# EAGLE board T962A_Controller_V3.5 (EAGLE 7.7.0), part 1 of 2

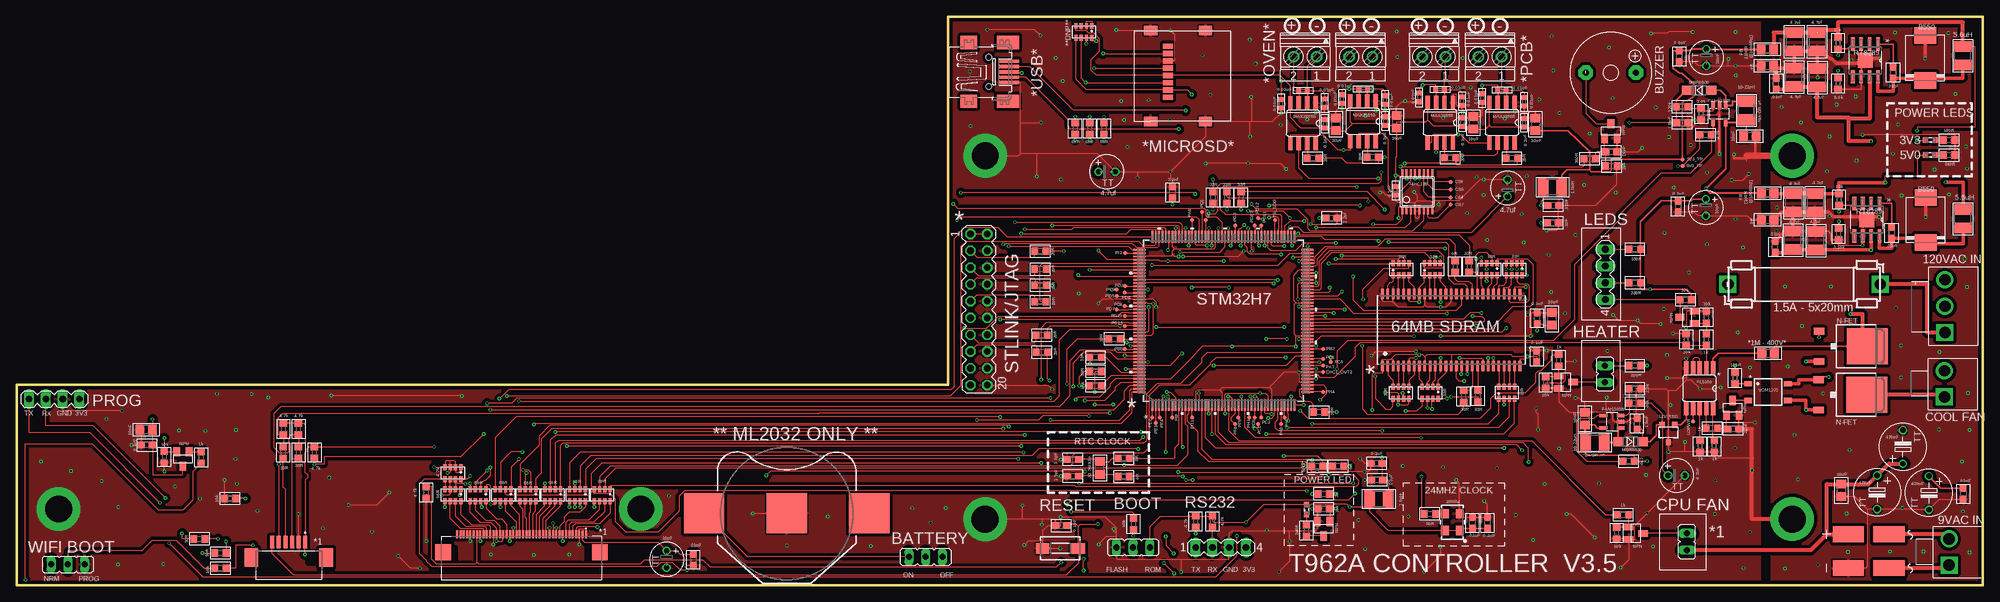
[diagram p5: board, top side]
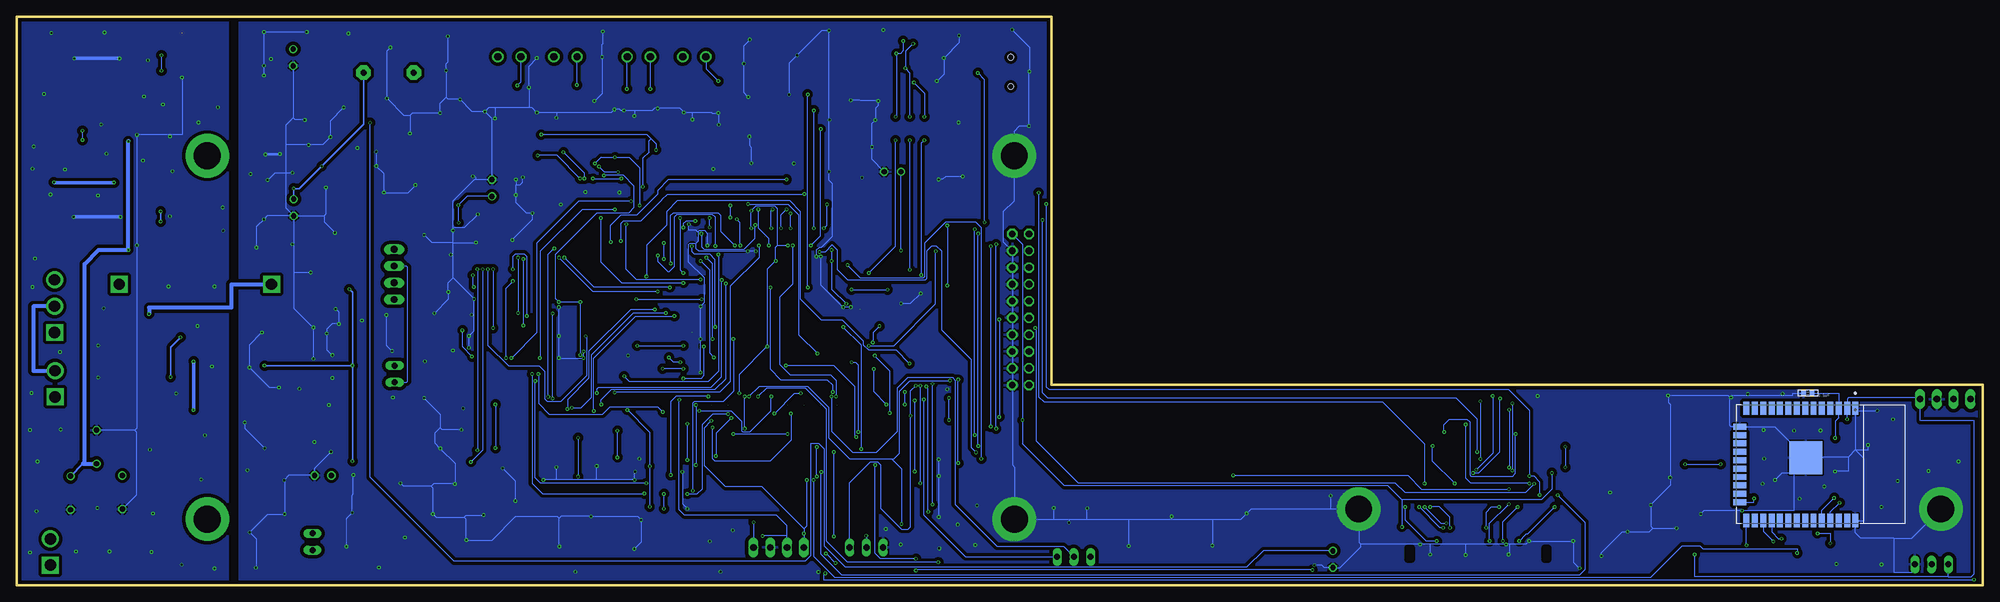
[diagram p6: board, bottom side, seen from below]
Size 297.71 x 86.11 mm. Coordinates in mm from the lower left corner, seen from the top.
Outline: 297.71,0 0,0 0,30.35 141,30.35 141,86.11 297.71,86.11 297.71,0
Copper layers (1*16): Top 0.035559375mm / dielectric 1.6mm / Bottom 0.035559375mm
Design rules "oshpark-2layer-tented": minimum track width 6mil, minimum drill 10mil, track to track 6mil, track to pad 6mil, pad to pad 6mil, via to via 6mil, smd to smd 6mil, copper to edge 15mil, drill to drill 6mil, minimum pad ring 5mil, minimum via ring 5mil, stop-mask expansion 2.5mil, vias tented up to drill 20mil, thermal gap 10mil

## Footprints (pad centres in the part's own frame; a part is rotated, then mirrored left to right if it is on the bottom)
Z4-D = smd 2.4 x 4.7: AC1 2.55,-3.1; AC2 -2.55,-3.1; VDD 2.55,3.1; VSS -2.55,3.1
BATTCON_20MM = smd 6.07 x 6.07: 1 -12.5,0; 2 0,0; 3 12.5,0
TT5D7 = drill 0.813: + -2.54,0 | drill 0.813 octagon: - 2.54,0
C0603 = smd 1.1 x 1: 1 -0.85,0; 2 0.85,0
TT2D5 = drill 0.813: + -1.27,0 | drill 0.813 octagon: - 1.27,0
C0805 = smd 1.3 x 1.5: 1 -0.95,0; 2 0.95,0
C0402 = smd 0.7 x 0.9: 1 -0.65,0; 2 0.65,0
C1210 = smd 1.6 x 2.7: 1 -1.4,0; 2 1.4,0
SOD123 = smd 1.4 x 1.4: A -1.9,0; C 1.9,0
FUSE_HOLDER_5X20MM_1.78MM = drill 1.707 square: 1 -2.565,0; 2 20.498,0.025
SOT23-3 = smd 0.8 x 0.9: 1 -0.95,-1; 2 0.95,-1; 3 0,1.659
TSSOP16 = smd 0.305 x 0.991: 1 -2.275,-2.918; 2 -1.625,-2.918; 3 -0.975,-2.918; 4 -0.325,-2.918; 5 0.325,-2.918; 6 0.975,-2.918; 7 1.625,-2.918; 8 2.275,-2.918; 9 2.275,2.918; 10 1.625,2.918; 11 0.975,2.918; 12 0.325,2.918; 13 -0.325,2.918; 14 -0.975,2.918; 15 -1.625,2.918; 16 -2.275,2.918
MOLEX_54104-4031-REV = smd 0.3 x 1.2: 1 9.75,0.6; 2 9.25,0.6; 3 8.75,0.6; 4 8.25,0.6; 5 7.75,0.6; 6 7.25,0.6; 7 6.75,0.6; 8 6.25,0.6; 9 5.75,0.6; 10 5.25,0.6; 11 4.75,0.6; 12 4.25,0.6; 13 3.75,0.6; 14 3.25,0.6; 15 2.75,0.6; 16 2.25,0.6; 17 1.75,0.6; 18 1.25,0.6; 19 0.75,0.6; 20 0.25,0.6; 21 -0.25,0.6; 22 -0.75,0.6; 23 -1.25,0.6; 24 -1.75,0.6; 25 -2.25,0.6; 26 -2.75,0.6; 27 -3.25,0.6; 28 -3.75,0.6; 29 -4.25,0.6; 30 -4.75,0.6; 31 -5.25,0.6; 32 -5.75,0.6; 33 -6.25,0.6; 34 -6.75,0.6; 35 -7.25,0.6; 36 -7.75,0.6; 37 -8.25,0.6; 38 -8.75,0.6; 39 -9.25,0.6; 40 -9.75,0.6 | smd 2.4 x 2.4: FITTING_NAIL_1 -11.85,-2.1; FITTING_NAIL_2 11.85,-2.1
KK41791-4020_2-PIN = drill 1.707 square: 1 -1.981,0 | drill 1.707: 2 1.981,0
MOLEX_52271-0679_REV = smd 0.6 x 1.9: 1 2.5,3.5; 2 1.5,3.5; 3 0.5,3.5; 4 -0.5,3.5; 5 -1.5,3.5; 6 -2.5,3.5 | smd 2.1 x 2.8: FITTING_NAIL_1 -5.65,1.15; FITTING_NAIL_2 5.65,1.15
KK41791-4020_3-PIN = drill 1.707 square: 1 -1.981,0 | drill 1.707: 2 1.981,0; 3 5.994,0
JP2_NOLABEL = drill 0.914 long: 1 -2.54,0; 2 0,0; 3 2.54,0
JP1 = drill 0.914 long: 1 0,-1.27; 2 0,1.27
L0805 = smd 1.3 x 1.5: 1 -0.95,0; 2 0.95,0
R1210 = smd 1.6 x 2.7: 1 -1.4,0; 2 1.4,0
SML0603 = smd 0.8 x 0.8: A 0.75,0; C -0.75,0
R0603 = smd 1 x 1.1: 1 -0.85,0; 2 0.85,0
R0805 = smd 1.3 x 1.5: 1 -0.95,0; 2 0.95,0
742-8NS-REV = smd 0.5 x 0.9: 1 1.2,-0.9; 2 0.4,-0.9; 3 -0.4,-0.9; 4 -1.2,-0.9; 5 -1.2,0.9; 6 -0.4,0.9; 7 0.4,0.9; 8 1.2,0.9
742-8NS = smd 0.5 x 0.9: 1 -1.2,-0.9; 2 -0.4,-0.9; 3 0.4,-0.9; 4 1.2,-0.9; 5 1.2,0.9; 6 0.4,0.9; 7 -0.4,0.9; 8 -1.2,0.9
DTSM-3 = smd 2 x 1.6: 1 -2.7,0; 2 2.7,0
YHE12-XX-7.6MM = drill 0.914 pad 2.159 octagon: + 3.81,0.025; - -3.81,0.025
MA10-2 = drill 1.016 octagon: 1 -11.43,-1.27; 2 -11.43,1.27; 3 -8.89,-1.27; 4 -8.89,1.27; 5 -6.35,-1.27; 6 -6.35,1.27; 7 -3.81,-1.27; 8 -3.81,1.27; 9 -1.27,-1.27; 10 -1.27,1.27; 11 1.27,-1.27; 12 1.27,1.27; 13 3.81,-1.27; 14 3.81,1.27; 15 6.35,-1.27; 16 6.35,1.27; 17 8.89,-1.27; 18 8.89,1.27; 19 11.43,-1.27; 20 11.43,1.27
MA04-1-VANILLA = drill 1.016 long: 1 -3.81,0; 2 -1.27,0; 3 1.27,0; 4 3.81,0
MA04-1 = drill 1.016 long: 1 -3.81,0; 2 -1.27,0; 3 1.27,0; 4 3.81,0
SOT23-BEC = smd 1 x 1.4: B -0.95,-1.1; C 0,1.1; E 0.95,-1.1
TP06R = smd 0.6 x 0.6: TP 0,0
LQFP176-24X24MM-M = smd 1.778 x 0.279: 1 -12.725,10.75; 2 -12.725,10.25; 3 -12.725,9.75; 4 -12.725,9.25; 5 -12.725,8.75; 6 -12.725,8.25; 7 -12.725,7.75; 8 -12.725,7.25; 9 -12.725,6.75; 10 -12.725,6.25; 11 -12.725,5.75; 12 -12.725,5.25; 13 -12.725,4.75; 14 -12.725,4.25; 15 -12.725,3.75; 16 -12.725,3.25; 17 -12.725,2.75; 18 -12.725,2.25; 19 -12.725,1.75; 20 -12.725,1.25; 21 -12.725,0.75; 22 -12.725,0.25; 23 -12.725,-0.25; 24 -12.725,-0.75; 25 -12.725,-1.25; 26 -12.725,-1.75; 27 -12.725,-2.25; 28 -12.725,-2.75; 29 -12.725,-3.25; 30 -12.725,-3.75; 31 -12.725,-4.25; 32 -12.725,-4.75; 33 -12.725,-5.25; 34 -12.725,-5.75; 35 -12.725,-6.25; 36 -12.725,-6.75; 37 -12.725,-7.25; 38 -12.725,-7.75; 39 -12.725,-8.25; 40 -12.725,-8.75; 41 -12.725,-9.25; 42 -12.725,-9.75; 43 -12.725,-10.25; 44 -12.725,-10.75; 89 12.725,-10.75; 90 12.725,-10.25; 91 12.725,-9.75; 92 12.725,-9.25; 93 12.725,-8.75; 94 12.725,-8.25; 95 12.725,-7.75; 96 12.725,-7.25; 97 12.725,-6.75; 98 12.725,-6.25; 99 12.725,-5.75; 100 12.725,-5.25; 101 12.725,-4.75; 102 12.725,-4.25; 103 12.725,-3.75; 104 12.725,-3.25; 105 12.725,-2.75; 106 12.725,-2.25; 107 12.725,-1.75; 108 12.725,-1.25; 109 12.725,-0.75; 110 12.725,-0.25; 111 12.725,0.25; 112 12.725,0.75; 113 12.725,1.25; 114 12.725,1.75; 115 12.725,2.25; 116 12.725,2.75; 117 12.725,3.25; 118 12.725,3.75; 119 12.725,4.25; 120 12.725,4.75; 121 12.725,5.25; 122 12.725,5.75; 123 12.725,6.25; 124 12.725,6.75; 125 12.725,7.25; 126 12.725,7.75; 127 12.725,8.25; 128 12.725,8.75; 129 12.725,9.25; 130 12.725,9.75; 131 12.725,10.25; 132 12.725,10.75 | smd 0.279 x 1.778: 45 -10.75,-12.725; 46 -10.25,-12.725; 47 -9.75,-12.725; 48 -9.25,-12.725; 49 -8.75,-12.725; 50 -8.25,-12.725; 51 -7.75,-12.725; 52 -7.25,-12.725; 53 -6.75,-12.725; 54 -6.25,-12.725; 55 -5.75,-12.725; 56 -5.25,-12.725; 57 -4.75,-12.725; 58 -4.25,-12.725; 59 -3.75,-12.725; 60 -3.25,-12.725; 61 -2.75,-12.725; 62 -2.25,-12.725; 63 -1.75,-12.725; 64 -1.25,-12.725; 65 -0.75,-12.725; 66 -0.25,-12.725; 67 0.25,-12.725; 68 0.75,-12.725; 69 1.25,-12.725; 70 1.75,-12.725; 71 2.25,-12.725; 72 2.75,-12.725; 73 3.25,-12.725; 74 3.75,-12.725; 75 4.25,-12.725; 76 4.75,-12.725; 77 5.25,-12.725; 78 5.75,-12.725; 79 6.25,-12.725; 80 6.75,-12.725; 81 7.25,-12.725; 82 7.75,-12.725; 83 8.25,-12.725; 84 8.75,-12.725; 85 9.25,-12.725; 86 9.75,-12.725; 87 10.25,-12.725; 88 10.75,-12.725; 133 10.75,12.725; 134 10.25,12.725; 135 9.75,12.725; 136 9.25,12.725; 137 8.75,12.725; 138 8.25,12.725; 139 7.75,12.725; 140 7.25,12.725; 141 6.75,12.725; 142 6.25,12.725; 143 5.75,12.725; 144 5.25,12.725; 145 4.75,12.725; 146 4.25,12.725; 147 3.75,12.725; 148 3.25,12.725; 149 2.75,12.725; 150 2.25,12.725; 151 1.75,12.725; 152 1.25,12.725; 153 0.75,12.725; 154 0.25,12.725; 155 -0.25,12.725; 156 -0.75,12.725; 157 -1.25,12.725; 158 -1.75,12.725; 159 -2.25,12.725; 160 -2.75,12.725; 161 -3.25,12.725; 162 -3.75,12.725; 163 -4.25,12.725; 164 -4.75,12.725; 165 -5.25,12.725; 166 -5.75,12.725; 167 -6.25,12.725; 168 -6.75,12.725; 169 -7.25,12.725; 170 -7.75,12.725; 171 -8.25,12.725; 172 -8.75,12.725; 173 -9.25,12.725; 174 -9.75,12.725; 175 -10.25,12.725; 176 -10.75,12.725
MODULE_ESP32-WROOM-32D = smd 2 x 0.9: 1 -8.5,5.26; 2 -8.5,3.99; 3 -8.5,2.72; 4 -8.5,1.45; 5 -8.5,0.18; 6 -8.5,-1.09; 7 -8.5,-2.36; 8 -8.5,-3.63; 9 -8.5,-4.9; 10 -8.5,-6.17; 11 -8.5,-7.44; 12 -8.5,-8.71; 13 -8.5,-9.98; 14 -8.5,-11.25; 25 8.5,-11.25; 26 8.5,-9.98; 27 8.5,-8.71; 28 8.5,-7.44; 29 8.5,-6.17; 30 8.5,-4.9; 31 8.5,-3.63; 32 8.5,-2.36; 33 8.5,-1.09; 34 8.5,0.18; 35 8.5,1.45; 36 8.5,2.72; 37 8.5,3.99; 38 8.5,5.26 | smd 0.9 x 2: 15 -5.715,-12.25; 16 -4.445,-12.25; 17 -3.175,-12.25; 18 -1.905,-12.25; 19 -0.635,-12.25; 20 0.635,-12.25; 21 1.905,-12.25; 22 3.175,-12.25; 23 4.445,-12.25; 24 5.715,-12.25 | smd 5 x 5: 39 -1,-2.24
SOT23-5L = smd 0.55 x 1.2: 1 -0.95,-1.3; 2 0,-1.3; 3 0.95,-1.3; 4 0.95,1.3; 5 -0.95,1.3
SO08 = smd 0.66 x 2.032: 1 -1.905,-3.073; 2 -0.635,-3.073; 3 0.635,-3.073; 4 1.905,-3.073; 5 1.905,3.073; 6 0.635,3.073; 7 -0.635,3.073; 8 -1.905,3.073
SOIC127P600X175-9N = smd 1.981 x 0.559: 1 -2.464,1.905; 2 -2.464,0.635; 3 -2.464,-0.635; 4 -2.464,-1.905; 5 2.464,-1.905; 6 2.464,-0.635; 7 2.464,0.635; 8 2.464,1.905 | smd 2.286 x 2.286: 9 0,0
DO214AB-SMC = smd 2.5 x 3.3: A 3.4,0; C -3.4,0
SOP10 = smd 0.66 x 2.032: 1 -2.057,-3.073; 2 -1.041,-3.073; 3 -0.025,-3.073; 4 0.991,-3.073; 5 2.007,-3.073; 6 2.007,3.073; 7 0.991,3.073; 8 -0.025,3.073; 9 -1.041,3.073; 10 -2.057,3.073
DPACK_3 = smd 1 x 1.6: 1 -2.28,-4.8; 3 2.28,-4.8 | smd 5.4 x 6.2: 4 0,2.5
SOP04 = smd 0.8 x 1.2: 1 -1.27,-3; 2 1.27,-3; 3 1.27,3; 4 -1.27,3
TSOP54 = smd 0.4 x 1.6: 1 -10.4,-5.45; 2 -9.6,-5.45; 3 -8.8,-5.45; 4 -8,-5.45; 5 -7.2,-5.45; 6 -6.4,-5.45; 7 -5.6,-5.45; 8 -4.8,-5.45; 9 -4,-5.45; 10 -3.2,-5.45; 11 -2.4,-5.45; 12 -1.6,-5.45; 13 -0.8,-5.45; 14 0,-5.45; 15 0.8,-5.45; 16 1.6,-5.45; 17 2.4,-5.45; 18 3.2,-5.45; 19 4,-5.45; 20 4.8,-5.45; 21 5.6,-5.45; 22 6.4,-5.45; 23 7.2,-5.45; 24 8,-5.45; 25 8.8,-5.45; 26 9.6,-5.45; 27 10.4,-5.45; 28 10.4,5.45; 29 9.6,5.45; 30 8.8,5.45; 31 8,5.45; 32 7.2,5.45; 33 6.4,5.45; 34 5.6,5.45; 35 4.8,5.45; 36 4,5.45; 37 3.2,5.45; 38 2.4,5.45; 39 1.6,5.45; 40 0.8,5.45; 41 0,5.45; 42 -0.8,5.45; 43 -1.6,5.45; 44 -2.4,5.45; 45 -3.2,5.45; 46 -4,5.45; 47 -4.8,5.45; 48 -5.6,5.45; 49 -6.4,5.45; 50 -7.2,5.45; 51 -8,5.45; 52 -8.8,5.45; 53 -9.6,5.45; 54 -10.4,5.45
MOLEX:47219-2001 = smd 1.45 x 2: G1 13.75,0; G2 13.75,8.3; G3 0,8.3; G4 0,0 | smd 0.8 x 1.5: P1 10.08,2.6; P2 8.98,2.6; P3 7.88,2.6; P4 6.78,2.6; P5 5.68,2.6; P6 4.58,2.6; P7 3.48,2.6; P8 2.38,2.6
1751248 = drill 1.1 pad 1.7: 1 -1.75,-0.1; 2 1.75,-0.1
32005-201 = smd 3.1 x 0.5: 1 3,1.6; 2 3,0.8; 3 3,0; 4 3,-0.8; 5 3,-1.6 | smd 2.5 x 2: M1 -3,-4.45; M2 -3,4.45 | smd 3.3 x 2: M3 2.9,4.45; M4 2.9,-4.45 | hole 0.9: 0,2.2; 0,-2.2
OSCILLATOR-SMD-5X3.2 = smd 1.397 x 1.194: 1 -1.27,-1.1; 2 1.27,-1.1; 3 1.27,1.1; 4 -1.27,1.1

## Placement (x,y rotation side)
B1  Z4DGP406L-HF  [Z4-D]  280.39,5.18 90 top
BT1  [BATTCON_20MM]  116.61,10.9 0 top
C1  470uF  [TT5D7]  289.53,14 270 top
C2  0.1uF  [C0603]  205.89,18.47 180 top
C3  10uF  [TT2D5]  255.83,79.91 270 top
C4  0.01uF  [C0603]  205.97,15.98 180 top
C5  .1uf  [C0603]  158.17,9.04 180 top
C6  470uF  [TT5D7]  281.69,14.1 270 top
C7  10uF  [C0805]  276.28,14.38 270 top
C8  0.1uF  [C0603]  222.71,9.47 90 top
C9  2.2uF  [C0603]  175.01,59.49 90 top
C10  2.2uF  [C0603]  199.09,55.63 0 top
C11  10uF  [TT2D5]  255.75,57.2 270 top
C12  0.01uF  [C0603]  220.42,9.47 90 top
C13  .1uf  [C0603]  230.2,40.44 90 top
C14  .1uf  [C0603]  230.15,34.65 90 top
C15  1.0uF  [C0603]  252.17,70.03 0 top
C16  0.1uF  [C0603]  251.71,80.09 270 top
C17  0.1uF  [C0603]  251.54,57.35 270 top
C18  10uF  [C0805]  262.41,67.97 0 top
C19  0.01uF  [C0402]  203.89,75.16 180 top
C20  0.01uF  [C0402]  200.66,73.61 90 top
C21  0.01uF  [C0402]  207.19,73.46 90 top
C22  0.01uF  [C0402]  215.52,75.06 180 top
C23  0.01uF  [C0402]  212.37,73.86 90 top
C24  1.5pf  [C0603]  159.92,19.08 0 top
C25  1.5pf  [C0603]  159.92,16.56 0 top
C26  0.1uF  [C0603]  232.61,54.89 0 top
C27  22nf  [C0603]  259.89,23.7 180 top
C28  470uF  [TT5D7]  285.6,20.95 90 top
C29  0.01uF  [C0603]  232.66,57.53 0 top
C30  1.0uF  [C0603]  245.34,24.49 90 top
C31  0.1uF  [C0402]  208.79,59.74 270 top
C32  0.1uF  [C0402]  207.21,70.28 270 top
C33  0.1uF  [C0402]  218.87,70.13 270 top
C34  10uF  [C0805]  237.44,25.25 90 top
C35  0.1uF  [C0402]  228.24,70.03 270 top
C36  0.1uF  [C0402]  198.07,69.88 270 top
C37  4.7uF  [TT2D5]  251.31,16.64 0 top
C38  4.7uF  [TT2D5]  165.07,62.61 0 top
C39  4.7uF  [TT2D5]  225.73,60.15 90 top
C40  10uF  [TT2D5]  98.42,3.96 270 top
C41  .01uF  [C0603]  102.44,3.89 270 top
C42  10uF  [C0805]  232.46,40.34 90 top
C43  10uF  [C0805]  19.66,23.55 180 top
C44  0.1uF  [C0603]  19.74,21.23 180 top
C45  DNP  [C0603]  241.43,65.63 180 top
C46  10uF  [C0805]  199.72,69.8 270 top
C47  10uF  [C0805]  208.94,70.15 270 top
C48  0.01uF  [C0402]  191.44,72.92 90 top
C49  10uF  [C0805]  220.55,70.03 270 top
C50  .01uF  [C0603]  294.72,13.87 270 top
C51  10uF  [C0805]  229.97,69.8 270 top
C52  0.01uF  [C0402]  198.04,73 90 top
C53  0.01uF  [C0402]  194.77,74.88 180 top
C54  .01uF  [C0603]  284.1,77.62 270 top
C55  .01uF  [C0603]  266.4,75.95 90 top
C56  4.7uF  [C1210]  272.64,76.84 90 top
C57  4.7uF  [C1210]  269.09,76.91 90 top
C58  47uf  [C1210]  269.14,82.27 270 top
C59  47uf  [C1210]  272.59,82.27 270 top
C60  0.01uF  [C0402]  218.85,73.28 90 top
C61  0.01uF  [C0402]  224.89,74.98 180 top
C62  0.01uF  [C0402]  221.89,73.76 90 top
C63  0.01uF  [C0402]  228.24,73.2 90 top
C64  0.1uF  [C0402]  26.52,29.08 180 bottom
C88  .01uF  [C0603]  283.87,53.37 270 top
C89  .01uF  [C0603]  266.24,51.23 90 top
C90  4.7uF  [C1210]  272.41,52.17 90 top
C91  4.7uF  [C1210]  268.94,52.25 90 top
C92  47uf  [C1210]  272.29,57.94 270 top
C93  47uf  [C1210]  269.01,57.89 270 top
D1  MBR0520LT  [SOD123]  254.71,74.93 180 top
D2  MBR0520LT  [SOD123]  244.35,21.74 0 top
F1  FUSE  [FUSE_HOLDER_5X20MM_1.78MM]  261.67,45.57 0 top
IC1  TLV760SOT-23-3  [SOT23-3]  250.09,23.32 180 top
IC2  74138TSSOP  [TSSOP16]  212.06,59.56 0 top
J1  54104-4031MOLEX_54101_4031-REV  [MOLEX_54104-4031-REV]  76.45,7.11 0 top
J2  0026604020  [KK41791-4020_2-PIN]  292.58,5.05 90 top
J3  52271-0679_REVMOLEX_52271-0679-REV  [MOLEX_52271-0679_REV]  41.22,3.1 0 top
J4  0026604030  [KK41791-4020_3-PIN]  291.95,40.26 90 top
J5  0026604020  [KK41791-4020_2-PIN]  291.87,30.51 90 top
JP1  [JP2_NOLABEL]  169.04,5.74 0 top
JP2  [JP1]  240.46,32 0 top
JP3  [JP1]  252.88,6.6 180 top
JP4  [JP2_NOLABEL]  137.64,4.32 180 top
JP6  [JP2_NOLABEL]  7.77,3.17 180 top
L1  100R@100Mhz  [L0805]  265.1,59.36 180 top
L2  5.6uH  [R1210]  294.67,80.16 90 top
L3  5.6uH  [R1210]  294.69,55.47 90 top
L4  10uH  [R1210]  206.27,13.11 0 top
L6  100R@100Mhz  [L0805]  265.07,81.18 180 top
L8  10uH  [R1210]  232.54,60.27 180 top
LED1  [SML0603]  289.74,67.41 180 top
LED2  [SML0603]  195.3,11.48 90 top
LED5  [SML0603]  289.71,65.13 180 top
Q1  32.768Khz  [C0805]  164.01,17.78 90 top
R1  20R  [R0603]  154.99,50.57 180 top
R2  100R  [R0603]  292.56,67.41 0 top
R3  20R  [R0603]  155.02,47.88 180 top
R4  20R  [R0603]  155.02,45.42 180 top
R5  240R  [R0603]  292.58,65.13 180 top
R6  0R  [R0805]  265.1,55.37 180 top
R7  20R  [R0603]  154.99,42.95 180 top
R8  20R  [R0603]  155.19,37.87 180 top
R9  20R  [R0603]  155.24,35.31 180 top
R10  10k  [R0603]  163.35,30.23 0 top
R11  10k  [R0603]  169.09,9.3 90 top
R12  33R  [R0603]  219.94,48.29 270 top
R13  0R  [R0603]  167.61,19.25 180 top
R14  50R  [R0603]  213.97,10.82 0 top
R15  0R  [R0603]  217.78,48.29 270 top
R16  33R  [R0603]  181.13,58.7 90 top
R17  20R  [R0603]  205.33,64.8 180 top
R18  20R  [R0603]  217.04,64.72 180 top
R19  20R  [R0603]  226.39,64.64 180 top
R20  1k  [R0603]  256.67,23.77 0 top
R21  10k  [R0603]  252.78,37.24 90 top
R22  100R  [R0603]  245.01,33.27 180 top
R23  4.7k  [R0603]  178.51,9.65 270 top
R24  4.7k  [R0603]  181.05,9.65 270 top
R25  100R  [R0603]  260.17,31.39 90 top
R26  2.0k  [R0603]  245.01,29.77 0 top
R27  20R  [R0603]  196.27,64.67 180 top
R28  2k  [R0603]  197.92,13.84 180 top
R29  240R  [R0603]  195.3,8.33 270 top
R30  10k  [R0603]  197.92,11.61 0 top
R31  10K  [R0603]  275.77,82.07 270 top
R32  5.6k  [R0603]  275.77,75.95 270 top
R33  10K  [R0603]  275.92,58.42 270 top
R34  3.16k  [R0603]  275.84,53.16 270 top
R35  10k  [R0603]  241.45,63.47 180 top
R36  4k7  [R0603]  42.7,23.67 90 top
R37  4K7  [R0603]  255.7,68.22 0 top
R38  4k7  [R0603]  62.03,14.05 270 top
R39  0R  [R0805]  265.07,78.66 180 top
R40  1M  [R0805]  265.18,35.15 0 top
R41  4k7  [R0603]  40.41,23.67 90 top
R42  33R  [R0603]  221.23,28.65 90 top
R43  390R  [R0603]  238.18,64.59 180 top
R44  10k  [R0603]  255.83,40.59 90 top
R45  120k  [R0603]  252.17,72.47 180 top
R46  4K7  [R0603]  244.04,18.8 180 top
R47  80k  [R0603]  245.01,27.56 0 top
R48  68R  [R0603]  164.64,69.16 90 top
R49  68R  [R0603]  162.48,69.16 90 top
R50  68R  [R0603]  160.27,69.16 90 top
R51  33R  [R0603]  42.7,20.12 270 top
R52  1k  [R0603]  243.2,10.69 0 top
R53  10k  [R0603]  242.24,7.9 90 top
R54  1k  [R0603]  233.48,34.09 270 top
R55  10k  [R0603]  231.5,30.71 90 top
R56  330R  [R0603]  245.01,50.88 180 top
R57  330R  [R0603]  245.01,45.8 180 top
R58  10k  [R0603]  252.7,43.23 0 top
R59  0R  [R0603]  200.08,18.03 0 top
R60  DNP  [R0603]  196.93,18.03 0 top
R61  2.0k  [R0603]  255.04,71.32 270 top
R62  1k  [R0603]  254.86,21.06 90 top
R63  1k  [R0603]  257.02,21.06 90 top
R64  1k  [R0603]  255.83,37.24 90 top
R65  33R  [R0603]  40.39,20.12 270 top
R66  4k7  [R0603]  45.11,20.12 90 top
R67  33R  [R0603]  219.07,28.63 90 top
R68  33R  [R0603]  166.22,37.34 180 top
R69  33R  [R0603]  197.21,26.24 0 top
R70  33R  [R0603]  163.35,34.54 180 top
R71  33R  [R0603]  163.35,32.38 180 top
R72  33R  [R0603]  183.26,58.7 90 top
R73  33R  [R0603]  185.39,58.7 90 top
R74  0R  [R0603]  167.61,16.48 180 top
R75  10k  [R0603]  22.38,19.41 270 top
R76  10k  [R0603]  30.89,2.59 0 top
R77  10k  [R0603]  32.33,13.16 0 top
R78  50R  [R0603]  30.89,4.9 0 top
R79  1k  [R0603]  27.97,19.38 270 top
R80  50R  [R0603]  27.69,7.04 0 top
RN1  33R  [742-8NS-REV]  209.63,47.83 0 top
RN2  33R  [742-8NS-REV]  214.35,47.83 0 top
RN3  33R  [742-8NS-REV]  214.02,29.16 180 top
RN4  33R  [742-8NS-REV]  209.6,29.16 180 top
RN5  33R  [742-8NS]  225.6,29.16 0 top
RN6  4.7k  [742-8NS]  66.07,16.99 180 top
RN7  33R  [742-8NS]  226.75,47.83 180 top
RN8  33R  [742-8NS]  222.96,47.83 180 top
RN11  **DNP**  [742-8NS]  161.59,83.77 180 top
RN12  68R  [742-8NS-REV]  88.67,13.67 180 top
RN13  68R  [742-8NS-REV]  84.94,13.67 180 top
RN14  68R  [742-8NS-REV]  81.18,13.67 180 top
RN15  68R  [742-8NS-REV]  77.42,13.67 180 top
RN16  68R  [742-8NS-REV]  73.66,13.67 180 top
RN17  68R  [742-8NS-REV]  69.88,13.67 180 top
RN18  68R  [742-8NS-REV]  66.07,13.67 180 top
S1  DTSM-3  [DTSM-3]  158.04,5.61 0 top
SG1  YHE12-XX7.6MM  [YHE12-XX-7.6MM]  241.38,77.6 0 top
SV1  [MA10-2]  145.69,41.76 270 top
SV2  PROG  [MA04-1-VANILLA]  5.71,28.19 0 top
SV3  [MA04-1]  240.54,47.07 270 top
SV5  RS232  [MA04-1]  182.32,5.74 0 top
T1  BC817-16LT1SMD  [SOT23-BEC]  241.38,68.76 0 top
T2  BC817-16LT1SMD  [SOT23-BEC]  25.2,19.13 180 top
T3  BC817-16LT1SMD  [SOT23-BEC]  197.89,8.59 180 top
T4  BC817-16LT1SMD  [SOT23-BEC]  245.16,7.87 270 top
T5  BC817-16LT1SMD  [SOT23-BEC]  234.57,30.76 270 top
T6  BC817-16LT1SMD  [SOT23-BEC]  259.82,26.87 0 top
T7  BC817-16LT1SMD  [SOT23-BEC]  252.93,40.59 90 top
TP1  TPTP06R  [TP06R]  187.48,25.43 0 top
TP2  TPTP06R  [TP06R]  187.99,24.41 0 top
TP3  TPTP06R  [TP06R]  198.93,33.78 0 top
TP4  TPTP06R  [TP06R]  252.22,64.47 0 top
TP5  TPTP06R  [TP06R]  188.47,25.43 0 top
TP6  TPTP06R  [TP06R]  217.12,57.66 0 top
TP7  TPTP06R  [TP06R]  217.12,61.09 0 top
TP8  TPTP06R  [TP06R]  217.12,59.92 0 top
TP9  TPTP06R  [TP06R]  217.12,58.75 0 top
TP10  TPTP06R  [TP06R]  197.79,34.29 90 top
TP11  TPTP06R  [TP06R]  167.77,42.27 0 top
TP12  TPTP06R  [TP06R]  166.55,41.78 0 top
TP13  TPTP06R  [TP06R]  173.05,25.43 0 top
TP15  TPTP06R  [TP06R]  171.96,25.43 0 top
TP16  TPTP06R  [TP06R]  179.5,56.54 90 top
TP17  TPTP06R  [TP06R]  180.04,55.27 90 top
TP18  TPTP06R  [TP06R]  197.79,32.28 0 top
TP19  TPTP06R  [TP06R]  197.79,33.27 0 top
TP21  TPTP06R  [TP06R]  177.98,55.27 0 top
TP22  TPTP06R  [TP06R]  197.79,35.76 0 top
TP23  TPTP06R  [TP06R]  167.77,35.79 0 top
TP24  TPTP06R  [TP06R]  167.82,45.29 0 top
TP25  TPTP06R  [TP06R]  166.55,44.78 0 top
TP26  TPTP06R  [TP06R]  167.77,39.29 0 top
TP27  TPTP06R  [TP06R]  252.22,63.45 0 top
TP28  TPTP06R  [TP06R]  253.8,24.79 0 top
TP29  TPTP06R  [TP06R]  191.47,24.41 0 top
TP30  TPTP06R  [TP06R]  191.99,25.43 0 top
TP31  TPTP06R  [TP06R]  167.77,44.3 0 top
TP32  TPTP06R  [TP06R]  166.55,43.81 0 top
TP33  TPTP06R  [TP06R]  184.48,24.41 0 top
TP34  TPTP06R  [TP06R]  184.96,25.43 0 top
TP35  TPTP06R  [TP06R]  167.77,40.79 0 top
TP36  TPTP06R  [TP06R]  197.79,29.29 0 top
TP39  TPTP06R  [TP06R]  184.48,54.48 0 top
TP40  TPTP06R  [TP06R]  167.82,50.29 0 top
TP41  TPTP06R  [TP06R]  174.98,25.43 0 top
TP42  TPTP06R  [TP06R]  188.47,54.48 0 top
TP43  TPTP06R  [TP06R]  187.96,55.63 0 top
TP44  TPTP06R  [TP06R]  187.48,54.48 0 top
TP45  TPTP06R  [TP06R]  177.98,25.43 0 top
TP46  TPTP06R  [TP06R]  190.55,55.27 0 top
TP47  TPTP06R  [TP06R]  186.61,25.43 0 top
TP48  TPTP06R  [TP06R]  172.47,24.56 0 top
U1  STM32H7X3IITLQFP176-24X24MM-M  [LQFP176-24X24MM-M]  182.73,40.03 90 top
U2  ESP32-WROOM-32D  [MODULE_ESP32-WROOM-32D]  24.56,18.31 270 bottom
U$1  FAN5333ABSOT23-5  [SOT23-5L]  257.81,71.4 180 top
U$2  INDUCTOR-GENERIC1210-PKG  [R1210]  261.9,71.88 90 top
U$3  MAX31855  [SO08]  194.77,69.95 180 top
U$4  MAX31855  [SO08]  203.83,70.23 180 top
U$5  MAX31855  [SO08]  215.54,70.05 180 top
U$6  MAX31855  [SO08]  224.89,70.05 180 top
U$7  RT8289  [SOIC127P600X175-9N]  279.91,79.48 270 top
U$8  DIODE-SMC  [DO214AB-SMC]  288.98,79.83 90 top
U$9  RT8289  [SOIC127P600X175-9N]  280.14,55.35 270 top
U$10  FL5160SOP10  [SOP10]  254.79,29.82 180 top
U$11  N-PWR-MOSFETDPAK3  [DPACK_3]  277.65,28.85 270 top
U$12  N-PWR-MOSFETDPAK3  [DPACK_3]  277.67,36.2 270 top
U$13  DIODE-SMC  [DO214AB-SMC]  289.05,55.32 90 top
U$14  VOM1271  [SOP04]  265.15,29.26 270 top
U$15  AS4C32M16SB  [TSOP54]  217.2,38.66 0 top
U$16  INDUCTOR-GENERIC1210-PKG  [R1210]  238.94,21.62 0 top
U$17  FAN5333ABSOT23-5  [SOT23-5L]  241.55,24.77 90 top
U$19  MOLEX-47219-2001  [MOLEX:47219-2001]  171.7,83.97 270 top
X1  1751248  [1751248]  195.1,79.93 180 top
X2  1751248  [1751248]  203.5,79.93 180 top
X3  1751248  [1751248]  214.6,79.93 180 top
X4  1751248  [1751248]  223.09,79.93 180 top
X5  MINI-USB-32005-201  [32005-201]  147.19,77.72 0 top
Y1  OSCILLATORSMD-5X3  [OSCILLATOR-SMD-5X3.2]  217.37,9.58 90 top

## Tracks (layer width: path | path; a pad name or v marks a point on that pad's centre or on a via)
3V3_VDD  (via drill 0.25 pad 0.51)
  Top 0.152: 204.87,11.91 v201.85,11.91 201.37,12.39 196.1,12.39 195.94,12.23 LED2.A 188.81,12.23 v186.13,9.55 181.25,9.55 181.05,9.75 R24.1 R23.1 173.19,10.5 171.58,8.89 JP1.3 | 204.87,11.91 204.87,11.15 207.72,8.31 Y1.4 Y1.1 218.47,8.62 C12.1 C8.1 | 213.64,70.41 213.33,70.1 208.94,70.1 208.94,69.63 | 208.94,69.63 C32.2 207.21,69.88 202.23,69.88 | 161.99,83.92 161.19,83.92 | 161.19,83.92 160.39,83.92 RN11.4 | 161.19,83.92 RN11.3 | 161.99,83.92 162.35,83.57 163.14,83.57 163.96,82.75 163.96,80.87 162.66,79.58 162.66,78.01 163.47,77.19 U$19.P4 191.26,77.19 192.86,75.59 U$3.4 192.86,70.83 194.46,69.23 C36.2 199.72,69.23 C46.2 201.21,68.85 202.23,69.88 | v228.75,34.65 230.15,34.65 C14.1 | v228.75,34.65 226.57,34.65 226.31,34.9 217.2,34.9 | 217.2,34.9 213.51,34.9 213.21,34.59 | v162.36,25.68 155.37,25.68 154.71,25.02 v145.42,25.02 | 217.2,34.9 U$15.14 | v208.79,62.05 208.79,64.72 208.94,64.87 C47.2 208.94,69.63 | v208.79,62.05 C31.1 | 213.64,70.41 214.57,69.48 C33.2 219.56,69.48 219.56,69.08 C49.2 222.36,69.08 222.96,69.68 | 222.96,69.68 223.27,69.38 C35.2 228.93,69.38 228.93,68.85 C51.2 | 44.04,20.45 43.74,20.75 43.74,24.32 43.54,24.52 R36.2 R41.2 | 208.1,34.24 208.76,34.9 v212.34,34.9 212.9,34.9 213.21,34.59 | 204.87,11.91 L4.1 | 44.04,20.45 43.74,20.14 43.74,17.07 44.04,16.76 44.04,16.33 43.72,16.01 J3.1 43.66,6.6 v43.66,4.67 | 44.04,20.45 44.04,20.75 44.26,20.97 R66.2 63.22,20.97 v63.22,20.98 | v230.2,38.61 C13.1 230.94,39.59 231.14,39.38 C42.1 | 161.99,83.92 RN11.2 161.99,85.37 162.79,85.37 RN11.1 | 65.2,16.94 v65.28,17.02 65.51,17.02 65.76,17.27 65.76,17.89 RN6.3 65.67,18.88 65.68,18.9
  Top 0.152: 222.96,69.68 222.98,69.7 222.99,69.7 U$6.4 | 202.23,69.88 201.93,70.18 U$4.4 | 213.64,70.41 U$5.4 | 65.68,18.9 65.07,18.9 64.87,18.69 RN6.4 v63.22,17.88 | 65.68,18.9 66.26,18.9 66.47,18.69 RN6.2 66.47,17.09 67.27,17.09 RN6.1 | SV1.2 SV1.1 | v208.79,62.05 209.27,62.05 209.27,61.95 209.47,61.75 209.79,61.75 IC2.16 | v205.23,26.57 205.23,31.93 205.44,32.13 206.8,32.13 U$15.1 206.8,34.24 208.1,34.24 | v228.75,34.65 228.35,34.24 227.6,34.24 U$15.27 | 213.21,34.59 213.21,34.27 213.2,34.25 U$15.9 | 208.1,34.24 208.41,34.24 208.41,33.21 U$15.3 | v87.96,8.86 84.91,8.86 84.7,8.66 J1.4 | v212.34,42.9 210.97,42.9 210.8,43.08 U$15.49 | v201.85,18.03 R59.2 | v161.57,30.23 R10.1 | v215.6,42.9 | v215.6,42.9 U$15.43 | C44.1 20.61,21.23 | 20.61,21.23 C43.1 v20.61,25.15 v20.6,25.15 | 20.61,21.23 20.61,16.71 25.17,16.71 25.17,18.03 T2.C
  Top 0.203: 253.9,74.07 252.93,73.36 252.43,73.36 252.17,73.05 TP4.TP 241.48,64.47 241.48,62.89 241.3,62.59 238.38,62.59 238.18,62.89 | C51.2 234.9,68.85 238.18,65.67 238.18,62.89 | 238.18,62.89 234.75,62.89 233.94,62.18 L8.1
  Top 0.254: C16.1 250.72,80.94 250.72,78.31 251.79,77.5 252.15,77.5 253.9,75.9 253.9,74.07
  Top 0.305: L6.2 C3.+ 253.57,81.18 253.33,80.94 C16.1
  Bottom 0.152: JP1.3 171.58,15.52 168.4,18.69 167.34,18.69 166.93,18.29 166.93,11.66 163.75,8.48 162.76,8.48 162.36,8.89 v162.36,25.68 162.36,29.44 v161.57,30.23 | 87.96,12.93 90.12,15.09 139.07,15.09 145.42,21.44 v145.42,25.02 145.42,51.64 SV1.2 | v65.28,17.02 65.28,14.53 66.88,12.93 87.96,12.93 | v208.79,62.05 205.79,62.05 204.19,60.45 204.19,57.2 205,56.39 209.78,56.39 216.08,50.09 216.08,43.38 v215.6,42.9 v212.34,42.9 v212.34,34.9 | v186.13,9.55 SV5.4 | v228.75,34.65 230.2,36.09 v230.2,38.61 | v205.23,26.57 201.85,23.19 v201.85,18.03 v201.85,11.91 | 87.96,12.93 v87.96,8.86 | v63.22,20.98 v63.22,17.88 | v20.6,25.15 20.6,26.81 U2.2 20.57,28.17 20.37,28.37 9.53,28.37 SV2.4 9.53,24.92 1.35,24.92 1.35,1.78 1.78,1.35 5.23,1.35 | 5.23,1.35 JP6.3 | 5.23,1.35 43.66,1.35 v43.66,4.67
5V0_VDD  (via drill 0.25 pad 0.51)
  Top 0.152: R37.1 254.85,66.08 TP27.TP v251.51,63.45 | 261.9,69.98 U$2.1 261.9,70.93 | 261.9,67.97 C18.1 | v246.84,33.27 R22.1 | 237.54,24.3 C34.1
  Top 0.203: 261.9,69.98 261.9,67.97
  Top 0.254: 237.54,24.3 238.86,24.3 239.34,23.81 U$17.5 | U$16.1 237.54,19.99 237.94,19.71 244.89,19.71 R46.1 v246.84,18.8 | R58.2 253.55,44.03 252.76,44.83 v247.32,44.83 246.01,44.83 245.86,44.98 R57.1 R56.1 245.86,55.02 249.05,58.2 C17.1 253.53,58.2 253.8,58.47 C11.+ | U$1.5 258.76,63.08 v255.75,60.07 | v260.17,33.27 R25.2
  Top 0.305: 264.1,59.31 L1.2 256.46,59.36 v255.75,60.07 | U$16.1 237.54,24.3 | U$1.5 261.9,70.1 261.9,69.98
  Bottom 0.203: SG1.+ 245.19,69.77 v251.51,63.45 254.89,60.07 v255.75,60.07
  Bottom 0.254: C11.+ v255.75,60.07 | v246.84,33.27 v246.84,18.8 | v246.84,33.27 v260.17,33.27 | v247.32,44.83 246.84,44.35 v246.84,33.27
12V0_VDD
  Top 0.203: U$10.6 252.78,25.12 251.98,24.32 IC1.1
!CS0  (via drill 0.25 pad 0.51)
  Top 0.152: v206.15,61.57 195.73,61.57 194.13,63.17 U$3.6 | v210.44,61.57 | v210.44,61.57 IC2.15
  Bottom 0.152: v210.44,61.57 v206.15,61.57
!CS1
  Top 0.152: U$4.6 203.2,68.4 206.78,68.4 207.59,67.59 207.59,60.1 208,59.69 209.5,59.69 211.09,61.28 IC2.14
!CS2  (via drill 0.25 pad 0.51)
  Top 0.152: v214.91,65.56 U$5.6 | v211.73,61.57 v211.74,61.57 IC2.13
  Bottom 0.152: v211.73,61.57 211.73,62.38 v214.91,65.56
!CS3  (via drill 0.25 pad 0.51)
  Top 0.152: v218.82,65.08 223.85,65.08 224.26,65.48 U$6.6 | v212.39,61.57 IC2.12
  Bottom 0.152: v212.39,61.57 215.9,65.08 v218.82,65.08
!CS4
  Top 0.152: TP9.TP 213.84,58.75 213.04,59.55 IC2.11
!CS5
  Top 0.152: TP8.TP 214.5,59.92 213.69,60.73 IC2.10
!CS6
  Top 0.152: TP7.TP 214.76,61.09 214.34,61.5 IC2.9
!CS7
  Top 0.152: TP6.TP 215.06,55.6 213.89,55.6 213.69,55.8 IC2.7
!TP_INT  (via drill 0.25 pad 0.51)
  Top 0.152: v70.76,22.94 67.27,19.45 46.58,19.45 46.58,18.34 v45.11,18.34 R66.1 | v170.28,23.24 v81.58,23.24 | v39.73,18.34 39.73,7.09 39.72,7.09 J3.5 | v171.3,33.78 U1.167
  Bottom 0.152: v81.58,23.24 v81.59,23.25 81.59,24.33 80.78,25.15 78.11,25.15 77.7,24.74 77.7,16.74 77.5,16.54 71.17,16.54 70.76,16.94 v70.76,22.94 | v171.3,33.78 170.69,33.78 170.28,33.38 v170.28,23.24 | v45.11,18.34 v39.73,18.34
A0  (via drill 0.25 pad 0.51)
  Top 0.152: v196.16,19 181.08,19 179.48,20.6 U1.16 | v196.16,24.46 222.81,24.46 224.4,26.05 RN5.1
  Bottom 0.152: v196.16,24.46 v196.17,24.46 v196.17,19 v196.16,19
A1  (via drill 0.25 pad 0.51)
  Top 0.152: v225.2,20.78 181.58,20.78 179.98,22.38 U1.17 | v225.2,27.38 v225.2,27.39 RN5.2
  Bottom 0.152: v225.2,27.38 v225.2,20.78
A2  (via drill 0.25 pad 0.51)
  Top 0.152: v192.33,23.9 224.41,23.9 226,25.49 RN5.3 | v180.47,26.01 180.48,26.02 U1.18
  Bottom 0.152: v180.47,26.01 180.47,21.97 183.64,18.8 191.92,18.8 192.33,19.2 v192.33,23.9
A3  (via drill 0.25 pad 0.51)  (1 unrouted)
  Top 0.152: v180.98,22.94 U1.19 | v189.18,22.94 225.2,22.94 226.8,24.54 RN5.4
  Bottom 0.152: v189.18,22.94 v180.98,22.94
A4  (via drill 0.25 pad 0.51)
  Top 0.152: v227.94,20.45 227.13,21.26 183.08,21.26 181.48,22.86 U1.20 | v227.94,47.85 v227.95,47.86 RN7.1
  Bottom 0.152: v227.94,47.85 v227.94,20.45
A5  (via drill 0.25 pad 0.51)
  Top 0.152: v228.9,18.69 228.9,20.75 228.09,21.56 183.57,21.56 181.98,23.15 U1.21 | v227.15,47.85 v227.15,47.86 RN7.2
  Bottom 0.152: v227.15,47.85 227.15,20.45 v228.9,18.69
A6  (via drill 0.25 pad 0.51)
  Top 0.152: v226.34,47.85 v226.35,47.86 RN7.3 | v211.56,37.72 197.51,37.72 196.57,36.78 U1.60
  Bottom 0.152: v211.56,37.72 211.38,37.54 211.38,31.75 215.34,27.79 217.3,27.79 217.7,28.19 217.7,32.33 218.5,33.13 223.16,33.13 226.34,36.31 v226.34,47.85
A7  (via drill 0.25 pad 0.51)  (1 unrouted)
  Top 0.152: v225.55,38.96 224.87,38.28 U1.63 | v225.55,47.85 225.55,48.61 225.55,48.62 RN7.4
  Bottom 0.152: v225.55,47.85 v225.55,38.96
A8
  Top 0.152: RN8.1 224.16,49.43 228.73,49.43 229.54,48.62 229.54,42.57 229.13,42.16 226.49,42.16 223.11,38.78 U1.64
A9  (via drill 0.25 pad 0.51)
  Top 0.152: v220.95,49.43 220.95,49.99 221.36,50.39 222.55,50.39 223.36,49.59 RN8.2 | v220.95,39.34 220.89,39.28 U1.65
  Bottom 0.152: v220.95,39.34 v220.95,49.43
A10  (via drill 0.25 pad 0.51)
  Top 0.152: v220.47,40.77 221.84,40.77 222.25,40.36 222.25,40.03 222.05,39.83 198.96,39.83 198.91,39.78 U1.66 | v222.55,47.85 v222.56,47.86 RN8.3
  Bottom 0.152: v222.55,47.85 222.55,49.81 222.15,50.22 220.88,50.22 220.47,49.81 v220.47,40.77
A11  (via drill 0.25 pad 0.51)
  Top 0.152: v221.77,41.25 220.04,41.25 219.07,40.28 U1.67 | v221.77,49.61 v221.76,49.6 RN8.4
  Bottom 0.152: v221.77,49.61 v221.77,41.25
A12  (via drill 0.25 pad 0.51)
  Top 0.152: v185.88,54.53 185.22,53.87 184.98,53.87 U1.106 | v194.03,53.24 194.18,53.09 218.34,53.09 219.94,51.49 R12.1
  Bottom 0.152: v194.03,53.24 194.03,51.28 193.62,50.88 187.58,50.88 185.88,52.58 v185.88,54.53
A13  (1 unrouted)
  Top 0.152: TP39.TP U1.107
A14  (via drill 0.25 pad 0.51)
  Top 0.152: v185.39,56.92 R73.1 | v183.82,51.46 183.98,51.62 U1.108
  Bottom 0.152: v183.82,51.46 183.82,52.48 185.39,54.05 v185.39,56.92
A15  (via drill 0.25 pad 0.51)
  Top 0.152: v183.26,56.92 R72.1 | v183.46,54.05 183.48,54.04 U1.109
  Bottom 0.152: v183.46,54.05 183.46,56.72 v183.26,56.92
A16
  Top 0.152: TP42.TP 188.48,54.47 U1.99
A17  (via drill 0.25 pad 0.51)
  Top 0.152: v188.67,55.42 188.16,55.42 TP43.TP | v188.14,51.46 187.98,51.62 U1.100
  Bottom 0.152: v188.14,51.46 188.14,54.89 v188.67,55.42
A18
  Top 0.152: TP44.TP | TP44.TP U1.101
A19
  Top 0.152: TP48.TP 172.49,24.58 172.49,25.93 172.48,25.94 U1.2
A23
  Top 0.152: TP15.TP 171.98,25.45 U1.1
A24
  Top 0.152: U1.156 170,39.29 TP26.TP
A_3V3  (via drill 0.25 pad 0.51)  (1 unrouted)
  Top 0.152: v287.73,68.81 287.73,69.34 296.44,69.34 296.44,81.56 L2.2 | v287.73,67.41 LED1.A
  Top 0.61: L2.2 294.67,85.22 275.77,85.22 275.77,84.05 | 275.77,84.05 R31.1 | 275.77,84.05 273.1,84.05 arc-90 272.72,83.67 C58.1 266.02,83.67 L6.1
  Bottom 0.152: v287.73,68.81 v287.73,67.41
A_5V0  (via drill 0.25 pad 0.51)
  Top 0.152: R33.1 275.92,59.26 | 272.81,59.27 272.75,59.34 C92.1 | C93.1 269.01,59.34 | v282.96,60.96 282.96,62.03 287.83,62.03 287.83,65.13 LED5.A
  Top 0.508: 272.81,59.27 R33.1 275.92,60.96 v282.96,60.96 | 269.01,59.34 C92.1 | L3.2 294.69,61.01 v292.05,61.01 | C93.1 266.12,59.29 L1.1
  Bottom 0.508: v292.05,61.01 arc-90 292,60.96 v282.96,60.96
AC_DC_IN  (via drill 0.25 pad 0.51)
  Top 0.152: v280.77,50.77 | C91.1 268.94,51.14
  Top 0.254: C1.+ 291.35,14.72 C50.1
  Top 0.406: 274.55,7.67 274.07,8.15 | 274.07,15.29 274.1,15.33
  Top 0.508: v280.77,50.77 C90.1 268.94,50.77 C91.1 268.47,50.38 C89.1 | v280.77,50.77 U$9.7 | C57.1 268.67,75.1 C55.1
  Top 0.61: B1.VDD 277.23,7.67 274.55,7.67 274.02,7.67 271.68,5.33 JP3.2 | C28.+ 283.46,18.41 C6.+ 280.38,15.33 C7.1 274.1,15.33 | 274.07,8.15 274.07,15.29 | v280.77,67.23 277.37,67.23 277.37,70.64 | 277.37,70.64 277.37,70.79 272.64,70.79 C56.1 269.09,75.44 C57.1 | U$7.7 280.54,70.64 277.37,70.64
  Bottom 0.254: C1.+ 287.66,18.41 287.4,18.67
  Bottom 0.61: 287.66,18.41 C28.+ | v280.77,67.23 v280.77,50.77 285.27,50.77 287.4,48.64 287.4,18.67
AC_IN1
  Top 0.61: J2.2 291.89,7.73 B1.AC1
AC_IN2
  Top 0.61: J2.1 292.14,2.63 B1.AC2
AGND  (via drill 0.25 pad 0.51)
  Top 0.152: C90.2 272.29,53.57 | C50.2 291.1,13.02 C1.- 286.79,11.45 286.69,11.56 C6.- 280.19,11.56 | 280.19,11.56 278.32,13.43 C7.2 | R34.2 275.84,51.49 v279.5,51.49 U$9.6 | 272.29,56.49 C92.2 | 272.66,76.87 v272.64,76.89 C56.2 | 268.94,56.49 C93.2 | 272.64,80.87 C59.2 | C57.2 269.14,78.31 | 280.19,11.56 280.19,2.84 279.97,2.63 B1.VSS | U$7.6 279.48,77.01 | 279.48,79.05 U$7.9 | v279.5,68.2 293.41,68.2 R2.2 293.43,67.41 R5.1
  Top 0.203: R34.2 275.81,52.35 274.7,52.35 274.7,53.14 274.27,53.57 C90.2 | 279.48,79.05 279.27,78.84 U$7.6 279.27,75.1 R32.2
  Top 0.508: C93.2 272.29,56.49 272.29,53.57 | C56.2 272.64,80.87 | 269.14,78.31 C58.2 C59.2 274.93,79.6 275.49,79.05 279.48,79.05 | U$9.9 279.7,55.78 | C92.2 274.27,56.54 275.03,55.78 279.7,55.78 | C57.2 266.4,78.31 | R39.1 266.02,78.31 266.4,78.31 | 266.4,78.31 C55.2 | R6.1 267.16,56.49 268.94,56.49 C91.2 267.81,53.65 C89.2 | 279.7,55.78 v281.99,55.78 | v289.05,55.78 U$13.A | U$7.9 279.91,79.76 v282.14,79.76 | v288.98,79.76 U$8.A
  Bottom 0.152: 279.81,23.49 279.5,23.8 v279.5,51.49 v279.5,68.2 272.64,68.2 v272.64,76.89 | C6.- 279.5,13.74 279.5,23.19 279.81,23.49 | 279.81,23.49 C28.-
  Bottom 0.508: v281.99,55.78 v289.05,55.78 | v282.14,79.76 v288.98,79.76
  other vias: 277.06,10.9 285.5,11.71 269.19,22.73 277.5,20.52 269.75,16.05 274.73,45.26 284.51,41.96 285.34,36.3 285.34,31.47 270.31,39.27 268.12,33.12 290.37,62.97 295.1,66.42 292.58,59.18 284.38,83.67 292.46,83.62 277.83,79.48 278.41,74.02 275.56,72.77 267.23,72.36 270.15,70.08 274.5,67.95 278.56,64.29 274.09,62.69 293.57,74.37 284.89,69.77 267.74,2.54 272.69,3.12 288.7,5.13 294.69,11.23 291.01,23.62 294.54,18.75 295.66,5 294.89,49.45 295.27,45.19 295.43,29.11 295.3,63.07 284.1,65.33 266.5,57.18 266.42,53.67 274.5,55.88 267.74,45.24 273.53,29.06 291.11,35.33 285.37,59 277.29,5.08 283.64,5.13 295.66,23.52
  pour Top (isolate 0.508): 265.71,86.11 297.71,86.11 297.71,0.25 265.71,0.25
  pour Bottom (isolate 0.508): 265.71,86.11 297.71,86.11 297.71,0.25 265.71,0.25
BOOT0  (via drill 0.25 pad 0.51)
  Top 0.152: v159.99,30.1 159.99,33.73 161.59,35.33 165.56,35.33 166.61,34.28 U1.166 | v159.69,11.15 168.88,11.15 169.09,10.95 R11.2
  Bottom 0.152: v159.69,11.15 159.69,29.79 v159.99,30.1
BUZZER  (via drill 0.25 pad 0.51)
  Top 0.152: v209.52,63.4 237.11,63.4 237.33,63.62 R43.2 | v180.52,56.29 181.51,56.29 181.91,56.69 181.91,60.43 182.32,60.83 206.22,60.83 206.63,61.24 v206.63,62.54 | v180.52,54.05 180.48,54.01 U1.115
  Bottom 0.152: v206.63,62.54 208.66,62.54 v209.52,63.4 | v180.52,54.05 v180.52,56.29
CLK
  Top 0.152: R14.2 214.82,10.85 Y1.3
CLK_24MHZ  (via drill 0.25 pad 0.51)
  Top 0.152: v212.7,16.46 212.7,10.82 R14.1 | v212.7,22.35 187.58,22.35 185.98,23.95 U1.29
  Bottom 0.152: v212.7,22.35 v212.7,16.46
CLK_RTC_IN  (1 unrouted)
  Top 0.152: R13.1 175.29,19.25 175.29,20.78 175.98,21.47 U1.9
CLK_RTC_OUT  (via drill 0.25 pad 0.51)
  Top 0.152: v176.56,20.93 176.48,20.93 U1.10 | v176.56,16.48 R74.1
  Bottom 0.152: v176.56,16.48 v176.56,20.93
CS  (via drill 0.25 pad 0.51)
  Top 0.152: RN11.5 160.39,76.6 162,74.99 U$19.P2 177.26,74.99 v177.93,74.32 | v183.57,45.11 v177.93,45.11 | v174.12,29.26 174.68,29.26 175.48,28.46 U1.8
  Bottom 0.152: v177.93,45.11 v177.93,74.32 | v174.12,29.26 174.12,30.28 174.93,31.09 181.97,31.09 183.57,32.69 v183.57,45.11
D0  (via drill 0.25 pad 0.51)
  Top 0.152: v205.71,31.65 205.71,28.3 207.31,26.7 208,26.7 208.4,27.1 RN4.8 | v191.44,50.09 186.77,50.09 186.36,50.49 186.36,51.1 185.98,51.49 U1.104
  Bottom 0.152: v191.44,50.09 191.44,32.41 193.04,30.81 204.88,30.81 v205.71,31.65
D1  (via drill 0.25 pad 0.51)
  Top 0.152: v207.16,29.21 208.99,29.21 209.2,29 RN4.7 | v185.32,51.46 185.48,51.62 U1.105
  Bottom 0.152: v185.32,51.46 185.32,49.61 189.66,45.26 189.66,30.81 191.26,29.21 v207.16,29.21
D2  (via drill 0.25 pad 0.51)
  Top 0.152: v190.96,46.2 190.88,46.28 U1.142 | v209.83,29.13 210,28.96 RN4.6
  Bottom 0.152: v209.83,29.13 209.83,29.79 209.63,30 192.56,30 190.96,31.6 v190.96,46.2
D3  (via drill 0.25 pad 0.51)
  Top 0.152: v190.32,45.72 190.26,45.78 U1.143 | v209.19,27.38 210.64,27.38 210.8,27.54 RN4.5
  Bottom 0.152: v209.19,27.38 209.19,28.09 207.59,29.69 191.92,29.69 190.32,31.29 v190.32,45.72
D4  (via drill 0.25 pad 0.51)
  Top 0.152: v198.12,40.77 198.11,40.78 U1.68 | v210.31,26.42 212.01,26.42 212.82,27.22 RN3.8
  Bottom 0.152: v210.31,26.42 210.31,34.42 203.96,40.77 v198.12,40.77
D5  (via drill 0.25 pad 0.51)
  Top 0.152: v199.42,41.25 199.38,41.28 U1.69 | v213.64,26.9 213.62,26.92 RN3.7
  Bottom 0.152: v213.64,26.9 212.22,26.9 210.62,28.5 210.62,34.9 204.27,41.25 v199.42,41.25
D6  (via drill 0.25 pad 0.51)
  Top 0.152: v214.3,26.72 214.3,28.02 214.42,28.14 RN3.6 | v201.09,41.76 201.07,41.78 U1.70
  Bottom 0.152: v201.09,41.76 204.72,41.76 211.07,35.41 211.07,31.32 214.3,28.1 v214.3,26.72
D7  (via drill 0.25 pad 0.51)
  Top 0.152: v216.56,41.15 202.44,41.15 202.03,41.55 202.03,41.68 200.43,43.28 U1.73 | v216.56,28.27 216.55,28.26 RN3.5
  Bottom 0.152: v216.56,28.27 v216.56,41.15
D8  (via drill 0.25 pad 0.51)
  Top 0.152: v215.57,49.61 215.57,48.86 215.55,48.84 RN2.8 | v200.66,44.48 199.97,43.78 U1.74
  Bottom 0.152: v200.66,44.48 210.44,44.48 v215.57,49.61
D9  (via drill 0.25 pad 0.51)
  Top 0.152: v214.76,49.61 214.76,48.85 214.75,48.84 RN2.7 | v198.81,45.11 v198.81,45.1 198.81,44.5 198.59,44.28 U1.75
  Bottom 0.152: v198.81,45.11 210.26,45.11 v214.76,49.61
D10
  Top 0.152: U1.76 197.33,44.78 197.54,44.98 197.54,48.79 199.14,50.39 213.16,50.39 213.95,49.6 RN2.6
D11
  Top 0.152: U1.77 197.03,45.28 197.23,45.48 197.23,49.1 198.83,50.7 215.21,50.7 216.05,49.86 216.05,48.18 215.9,48.03 213.15,48.03 RN2.5
D12  (via drill 0.25 pad 0.51)
  Top 0.152: v194.01,43.31 194.01,45.57 194.22,45.78 U1.78 | v203.86,43.31 v203.85,43.31 203.85,44.86 207.03,48.03 210.83,48.03 RN1.8
  Bottom 0.152: v203.86,43.31 v194.01,43.31
D13  (via drill 0.25 pad 0.51)
  Top 0.152: v200.61,49.91 209.63,49.91 210.03,49.51 RN1.7 | v191.9,51.36 190.2,51.36 189.98,51.58 U1.96
  Bottom 0.152: v191.9,51.36 191.9,55.7 192.3,56.11 197.79,56.11 198.2,55.7 198.2,48.21 199.01,47.4 200.61,49 v200.61,49.91
D14  (via drill 0.25 pad 0.51)
  Top 0.152: v199.69,51.82 194.74,51.82 193.6,50.67 189.89,50.67 189.48,51.09 U1.97 | v199.69,49.43 209.23,49.43 RN1.6
  Bottom 0.152: v199.69,49.43 v199.69,51.82
D15  (via drill 0.25 pad 0.51)
  Top 0.152: v188.98,51.46 188.98,52.09 U1.98 | v198.68,48.72 208.43,48.72 RN1.5
  Bottom 0.152: v198.68,48.72 198.68,56.01 198.27,56.41 191.52,56.41 191.11,56.01 191.11,53.59 v188.98,51.46
DAC1_OUT1
  Top 0.152: U$10.2 R64.1 R21.1 252.78,36.75 203.4,36.75 202.59,35.94 202.59,34.62 199.41,31.45 197.41,31.45 197.07,31.78 U1.50
DAC1_OUT2
  Top 0.152: TP18.TP 196.67,32.28 U1.51
FMC_NBL0  (via drill 0.25 pad 0.51)
  Top 0.152: v167.92,32.77 169.33,32.77 169.34,32.78 U1.169 | v163.25,27.38 v166.01,27.38 | v163.25,29.26 163.25,32.18 163.45,32.38 R71.1
  Bottom 0.152: v166.01,27.38 167.92,29.29 v167.92,32.77 | v163.25,29.26 v163.25,27.38
FMC_NBL1
  Top 0.152: R70.1 164.95,34.54 167.21,32.28 U1.170
GND  (via drill 0.25 pad 0.51, 4.06 pad 6.6)  (2 unrouted)
  Top 0.152: 196.94,11.61 T3.E 196.94,8.64 196.54,8.23 192.74,8.23 | v196.14,11.61 196.94,11.61 | 242.33,65.63 T1.E | 242.33,65.63 v243.26,65.63 245.54,65.63 v246.1,66.19 | 245.13,25.34 245.13,29.77 R26.2 249.78,29.77 250.09,29.46 251.18,29.46 252.78,31.06 | 243.9,24.77 244.48,25.34 245.13,25.34 | 213.21,42.42 212.9,42.11 209.18,42.11 208.4,42.9 | 208.4,42.9 206.96,42.9 206.8,43.06 U$15.54 | T4.E 245.01,6.92 245.01,9.07 C37.- | 192.74,8.23 184,8.23 183.59,7.82 SV5.3 183.59,3.99 176.3,3.99 | 176.3,3.99 166.65,3.99 166.5,4.14 JP1.1 166.5,7.34 | 154.46,65.33 163.63,65.33 C38.- 169.7,62.61 | 154.46,65.33 151.99,65.33 | C39.- v222.1,61.42 221.56,61.42 218.34,58.19 215.29,58.19 | 215.29,58.19 214.66,58.19 214.35,57.89 | v231.62,53.7 233.06,53.7 233.46,54.1 C26.2 233.46,57.53 C29.2 239.12,57.53 242.3,60.72 R35.1 v243.23,63.48 | 166.5,7.34 166.5,8.05 | 166.5,8.05 166.5,8.74 164.9,10.34 v158.09,10.34 v158.09,10.33 158.09,9.04 C5.2 | 261.98,64.18 261.98,64.64 261.98,65.02 | C5.2 157.32,9.8 157.11,10.01 155.22,10.01 | 155.22,10.01 152.3,10.01 | 152.3,10.01 v146.63,10.01 | 234.42,33.93 234.42,35.46 234.21,35.66 230.15,35.66 C14.2 229.49,35.5 229.24,35.75 v229.24,35.97 | 234.42,33.93 234.42,31.01 234.01,30.61 231.5,30.61 R55.1 233.47,29.86 T5.E 233.47,27.79 235.06,26.2 C34.2 | R6.2 262.61,55.37 262.05,55.93 C11.- 254.61,55.93 254.04,56.5 C17.2 | 169.7,62.61 v174.7,62.61 | 259.18,78.66 257.28,78.66 257.25,78.64 C3.- 254.58,78.64 253.99,79.24 C16.2 | 259.18,78.66 v260.27,78.66 R39.2 | 182.17,29.57 182.6,30 189.66,30 | 262.74,19.3 257.18,19.3 257.02,19.46 R63.1 R62.1 252.6,20.21 | 189.66,30 191.9,32.23 v194.16,32.23 194.16,30.94 194.31,30.78 U1.48
  Top 0.152: v111.46,10.9 BT1.2 | 208.4,42.9 U$15.52 | C23.1 209.74,73.21 208.94,72.42 C47.1 208.94,70.93 C32.1 207.21,72.01 v207.19,72.03 C21.1 | C5.2 156.13,9.04 155.34,8.25 155.34,6.66 | 155.34,6.66 S1.1 v158.04,5.61 | v146.66,65.02 151.69,65.02 151.99,65.33 | 245.13,25.34 C30.2 | 252.6,20.21 250.1,20.21 v250.09,20.22 IC1.3 | 211.74,57.89 209.19,57.89 208.79,58.29 C31.2 207.33,59.09 206.93,59.49 v206.45,59.49 | 252.78,38.12 v252.78,39.01 252.78,41.34 252.98,41.54 T7.E 255.83,41.54 R44.2 | C62.1 221.89,71.18 221.69,70.98 C49.1 220.55,70.78 C33.1 218.87,71.48 v218.95,71.55 218.95,72.03 218.85,72.03 C60.1 218.16,72.63 218.01,72.78 218.01,74.37 217.45,74.37 U$5.1 | 242.33,65.63 C45.1 | 196.94,11.61 R30.1 | 211.74,57.89 212.04,58.19 212.09,58.19 | 212.09,58.19 214.05,58.19 214.35,57.89 | v174.7,62.61 174.7,61.65 175.01,61.34 C9.2 | 213.21,42.42 213.51,42.11 v215.6,42.11 216.38,42.11 217.2,42.93 U$15.41 | C27.1 260.77,23.7 260.77,24.64 | 260.77,24.64 T6.E | T4.E 244.06,7.05 R53.1 | C36.1 198.07,70.75 C46.1 199.72,71.78 200.13,72.19 v200.66,72.19 C20.1 | C52.1 198.04,71.76 197.89,71.6 v196.67,71.6 U$3.1 | 228.24,71.7 v226.8,71.7 U$6.1 | 228.24,71.7 229.97,71.7 C51.1 | R60.1 196.08,17.2 v196.9,17.2 v204.06,17.2 204.62,17.2 205.04,17.62 C2.2 204.14,18.47 v203.43,19.18 | C15.2 253.02,69.29 253.67,69.29 254.08,69.7 v254.08,70.46 254.09,70.47 R61.2 255.04,71.25 257.4,71.25 257.81,71.65 U$1.2 | 228.24,71.7 C35.1 | v158.09,19.07 C24.1 | v195.94,54.66 199.72,54.66 199.94,54.88 C10.2 | 228.24,71.7 C63.1 | C48.1 v191.44,71.5 190.16,70.22 186.94,70.22 | 241.91,24.77 241.71,24.97 | 241.29,26.22 240.72,26.22
  Top 0.152: 240.72,26.22 237.44,26.22 C34.2 | v217.96,15.98 218.47,15.46 Y1.2 218.47,10.32 C12.2 C8.2 222.71,12.27 v222.17,12.8 | 151.99,65.33 151.99,70.05 | 151.99,70.05 151.99,76.12 X5.5 | 252.78,31.37 U$10.5 v252.78,34.31 | 252.78,31.37 252.78,31.06 | U$19.G2 180,67.91 v174.7,62.61 | U$19.G2 186.77,70.22 | 186.77,70.22 186.94,70.22 | v174.7,83.97 175.29,83.39 175.29,79.39 U$19.P6 | v174.7,83.97 U$19.G3 | v174.7,83.97 U$19.G4 166.57,83.97 v166.5,84.05 | 214.35,57.89 214.35,56.91 214.34,56.9 IC2.8 | 211.74,57.89 IC2.4 211.74,55.8 211.94,55.6 212.17,55.6 212.39,55.82 IC2.5 | U$19.G2 U$19.G1 | v211.86,34.42 210.97,34.42 210.8,34.24 U$15.6 | 213.21,42.42 213.2,42.43 U$15.46 | J1.1 86.2,8.56 85.2,8.56 J1.3 v85.2,6.21 v85.22,6.2 | 175.29,50.98 181.25,50.98 181.48,51.2 U1.113 | 182.17,29.57 178.69,29.57 178.48,29.35 U1.14 | 174.98,50.09 174.68,49.78 U1.135 | 189.66,30 189.97,29.69 U1.37 | 182.17,29.57 182.48,29.26 U1.22 | v186.99,50.57 186.98,50.59 U1.102 | 175.29,50.98 174.98,51.28 U1.126 | v193.14,51.46 192.98,51.62 U1.90 | v215.6,37.74 v229.24,37.74 229.24,41.08 229.44,41.29 C13.2 230.94,41.29 230.94,41.28 C42.2 | 174.98,50.09 174.98,50.67 175.29,50.98 | 174.98,50.09 175.29,49.78 v175.97,49.78 | v194.16,37.29 194.16,37.28 U1.61 | v176.63,49.78 185.01,49.78 v185.8,50.57 | v228.42,43.36 228.42,43.33 228.17,43.08 227.6,43.08 U$15.28 | v172.57,42.11 172.57,42.88 172.16,43.28 U1.148 164.41,43.28 v163.8,42.67 | v72.21,6.2 v72.2,6.21 J1.29 | v171.4,42.11 171.4,38.48 171.2,38.28 U1.158 | v101.22,3.05 101.23,3.04 C41.2 | v62.05,6.71 62.05,13.2 R38.2 | J3.2 v42.72,10.82 | v194.16,42.21 194.22,42.28 U1.71 | v158.09,16.56 C25.1
  Top 0.152: v204.14,15.98 C4.2 | v205.74,71.88 U$4.1 | v68.71,6.71 v68.7,6.71 J1.36 | v215.6,34.42 | v215.6,34.42 U$15.12 | v47.65,28.75 67.36,28.75 v67.44,28.68 | v155.02,83.24 154.15,84.1 v146.99,84.1 | v50.29,12.19 54.58,12.19 v56.44,14.05 | v192.23,63.02 191.34,63.91 v186.49,63.91 180.06,63.91 v180.01,63.86 | v253.77,83.77 250.19,83.77 249.96,83.54 v247.47,83.54 | v191.14,2.06 192.74,3.66 v192.74,6.68 192.74,8.23 | v215.54,5.87 215.54,4.47 v213.13,2.06 | v186.94,73.91 186.94,70.22 | T4.E 244.06,3.9 v242.85,2.69 | v61.09,2.59 59.66,2.59 v57.79,4.47 | v241.73,40.95 242.6,40.08 v245.44,40.08 245.95,39.57 v248.89,39.57 | 252.78,31.06 253.59,31.06 v254.89,29.77 257.28,29.77 257.48,29.97 v257.96,29.97 | v230.38,23.57 230.38,25.88 230.1,26.16 v230.1,26.82 | v234.67,10.82 235.36,10.82 v238.94,7.24 | v259.69,61.34 261.34,61.34 v262.26,62.26 | v154.46,61.87 154.46,65.33 | 155.34,6.66 153.14,6.66 v152.58,6.1 | 166.5,7.34 164.97,7.34 v163.83,6.2 | 151.99,70.05 v155.09,70.05 | R21.2 252.78,38.12 | 252.78,38.12 v250.75,38.12 | 252.78,31.37 v249.89,31.37 | C34.2 237.44,27.53 236.63,28.35 v235.99,28.35 | v263.17,24.64 260.77,24.64 | v186.77,67.92 186.77,70.22 | 240.72,26.22 v240.72,28.45 | 152.3,10.01 v152.3,12.12 | 176.3,3.99 v176.3,2.01 | 212.09,58.19 212.09,59.08 v211.61,59.56 | 252.6,20.21 v252.6,21.72 | 234.42,33.93 v235.86,33.93 | 259.18,78.66 v259.18,79.68 | 169.7,62.61 v169.7,61.7 | 166.5,8.05 166.12,8.05 v166.12,8.53 | 155.22,10.01 v155.22,9.2 | 215.29,58.19 v215.29,57.63 | SV1.20 156.18,30.33 v156.82,29.69 | v211.86,35.38 205.71,35.38 v205.13,34.8 | R77.1 v31.48,15.94 | v16,26.44 6.99,26.44 SV2.3 | C43.2 18.89,23.55 C44.2 v17.4,21.23
  Top 0.152: v22.38,17.25 R75.2
  Top 0.203: IC1.3 250.09,29.46
  Top 0.254: 243.9,24.77 U$17.2 241.91,24.77 | 241.71,24.97 241.71,25.81 241.29,26.22
  Top 0.406: 261.98,65.02 261.98,64.85 | C18.2 263.25,67.97 263.25,65.02 | 257.81,71.65 v257.81,65.3 | v260.02,65.23 260.02,64.64 261.98,64.64
  Top 0.61: v268.83,10.03 262.74,10.03 262.74,19.3 262.74,23.67 260.74,23.67 C27.1
  Top 1.016: v268.83,65.02 263.25,65.02 261.98,65.02
  Bottom 0.152: 231.62,46.56 v228.42,43.36 228.42,40.97 | 231.62,46.56 231.62,51.89 | 231.62,51.89 v231.62,53.7 231.62,54.18 | 231.62,54.18 231.62,58.24 228.45,61.42 228.14,61.42 | C11.- 255.75,47.37 | 255.75,47.37 255.75,41.99 v252.78,39.01 v252.78,34.31 | 98.76,11.56 v94.51,11.56 94.51,6.5 94.21,6.2 | 98.76,11.56 110.79,11.56 v111.46,10.9 112.34,10.01 116.66,10.01 | C11.- 256.9,57.07 256.9,62.46 | 256.9,62.46 256.9,66.68 | 256.9,66.68 256.9,69.7 255.83,70.76 | 228.14,61.42 C39.- 225.73,70.64 v226.8,71.7 | 194.82,51.82 195.73,51.82 195.94,51.61 195.94,48.95 193.52,46.53 193.52,42.85 v194.16,42.21 v194.16,37.29 v194.16,32.23 | v185.8,50.57 v186.99,50.57 194.41,50.57 194.82,50.98 194.82,51.82 | 71.73,6.2 69.22,6.2 v68.71,6.71 v62.05,6.71 62.03,6.71 62.03,3.53 v61.09,2.59 | 71.73,6.2 v72.21,6.2 78.33,6.2 | 78.33,6.2 83.72,6.2 | 83.72,6.2 v85.22,6.2 94.21,6.2 | 215.98,71.55 207.67,71.55 v207.19,72.03 206.38,72.03 206.22,71.88 v205.74,71.88 204.17,71.88 | 215.98,71.55 v218.95,71.55 219.74,72.34 220.14,72.34 | C3.- 255.83,70.76 | 94.21,6.2 94.21,5.87 97.38,2.69 C40.- 99.7,2.69 100.05,3.05 v101.22,3.05 | v226.8,71.7 226.16,72.34 225.27,72.34 | 225.27,72.34 220.14,72.34 | 228.42,40.97 228.42,38.56 v229.24,37.74 v229.24,35.97 | v196.9,17.2 196.9,12.37 v196.14,11.61 | v158.09,19.07 v158.09,16.56 v158.09,10.34 | 140.67,10.01 v146.63,10.01 146.63,17.91 146.96,18.24 SV1.20 SV1.18 SV1.16 SV1.14 SV1.12 SV1.10 SV1.8 SV1.6 SV1.4 148.26,51.94 148.26,56.64 146.66,58.24 v146.66,65.02 146.66,68.73 145.85,69.55 v144.42,69.55 144.42,77.72 v144.35,77.8 144.35,81.46 v146.99,84.1 | 140.67,10.01 138.38,10.01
